VERSION 5.7 ;
BUSBITCHARS "[]" ;
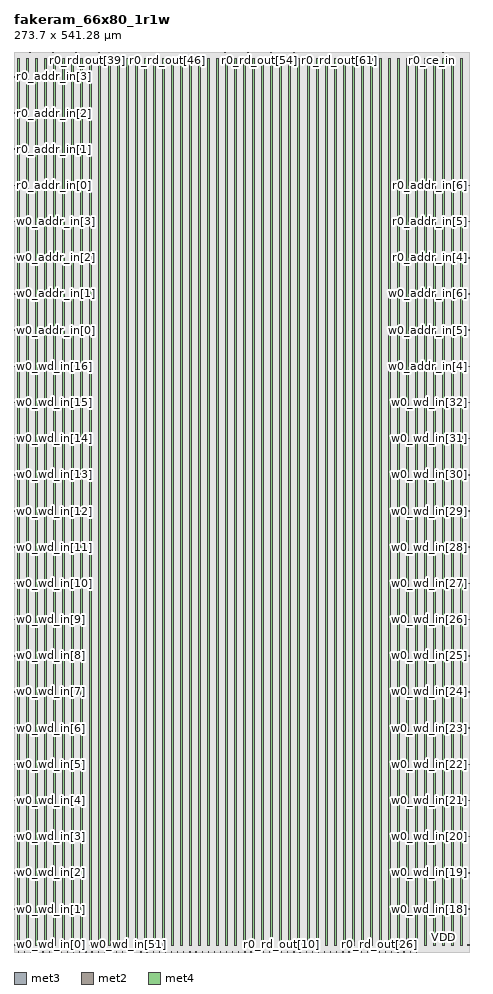
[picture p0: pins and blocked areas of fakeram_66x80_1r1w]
MACRO fakeram_66x80_1r1w
  FOREIGN fakeram_66x80_1r1w 0 0 ;
  SYMMETRY X Y R90 ;
  SIZE 273.700 BY 541.280 ;
  CLASS BLOCK ;
  PIN w0_wd_in[0]
    DIRECTION INPUT ;
    USE SIGNAL ;
    SHAPE ABUTMENT ;
    PORT
      LAYER met3 ;
      RECT 0.000 3.930 0.900 4.230 ;
    END
  END w0_wd_in[0]
  PIN w0_wd_in[1]
    DIRECTION INPUT ;
    USE SIGNAL ;
    SHAPE ABUTMENT ;
    PORT
      LAYER met3 ;
      RECT 0.000 25.690 0.900 25.990 ;
    END
  END w0_wd_in[1]
  PIN w0_wd_in[2]
    DIRECTION INPUT ;
    USE SIGNAL ;
    SHAPE ABUTMENT ;
    PORT
      LAYER met3 ;
      RECT 0.000 47.450 0.900 47.750 ;
    END
  END w0_wd_in[2]
  PIN w0_wd_in[3]
    DIRECTION INPUT ;
    USE SIGNAL ;
    SHAPE ABUTMENT ;
    PORT
      LAYER met3 ;
      RECT 0.000 69.210 0.900 69.510 ;
    END
  END w0_wd_in[3]
  PIN w0_wd_in[4]
    DIRECTION INPUT ;
    USE SIGNAL ;
    SHAPE ABUTMENT ;
    PORT
      LAYER met3 ;
      RECT 0.000 90.970 0.900 91.270 ;
    END
  END w0_wd_in[4]
  PIN w0_wd_in[5]
    DIRECTION INPUT ;
    USE SIGNAL ;
    SHAPE ABUTMENT ;
    PORT
      LAYER met3 ;
      RECT 0.000 112.730 0.900 113.030 ;
    END
  END w0_wd_in[5]
  PIN w0_wd_in[6]
    DIRECTION INPUT ;
    USE SIGNAL ;
    SHAPE ABUTMENT ;
    PORT
      LAYER met3 ;
      RECT 0.000 134.490 0.900 134.790 ;
    END
  END w0_wd_in[6]
  PIN w0_wd_in[7]
    DIRECTION INPUT ;
    USE SIGNAL ;
    SHAPE ABUTMENT ;
    PORT
      LAYER met3 ;
      RECT 0.000 156.250 0.900 156.550 ;
    END
  END w0_wd_in[7]
  PIN w0_wd_in[8]
    DIRECTION INPUT ;
    USE SIGNAL ;
    SHAPE ABUTMENT ;
    PORT
      LAYER met3 ;
      RECT 0.000 178.010 0.900 178.310 ;
    END
  END w0_wd_in[8]
  PIN w0_wd_in[9]
    DIRECTION INPUT ;
    USE SIGNAL ;
    SHAPE ABUTMENT ;
    PORT
      LAYER met3 ;
      RECT 0.000 199.770 0.900 200.070 ;
    END
  END w0_wd_in[9]
  PIN w0_wd_in[10]
    DIRECTION INPUT ;
    USE SIGNAL ;
    SHAPE ABUTMENT ;
    PORT
      LAYER met3 ;
      RECT 0.000 221.530 0.900 221.830 ;
    END
  END w0_wd_in[10]
  PIN w0_wd_in[11]
    DIRECTION INPUT ;
    USE SIGNAL ;
    SHAPE ABUTMENT ;
    PORT
      LAYER met3 ;
      RECT 0.000 243.290 0.900 243.590 ;
    END
  END w0_wd_in[11]
  PIN w0_wd_in[12]
    DIRECTION INPUT ;
    USE SIGNAL ;
    SHAPE ABUTMENT ;
    PORT
      LAYER met3 ;
      RECT 0.000 265.050 0.900 265.350 ;
    END
  END w0_wd_in[12]
  PIN w0_wd_in[13]
    DIRECTION INPUT ;
    USE SIGNAL ;
    SHAPE ABUTMENT ;
    PORT
      LAYER met3 ;
      RECT 0.000 286.810 0.900 287.110 ;
    END
  END w0_wd_in[13]
  PIN w0_wd_in[14]
    DIRECTION INPUT ;
    USE SIGNAL ;
    SHAPE ABUTMENT ;
    PORT
      LAYER met3 ;
      RECT 0.000 308.570 0.900 308.870 ;
    END
  END w0_wd_in[14]
  PIN w0_wd_in[15]
    DIRECTION INPUT ;
    USE SIGNAL ;
    SHAPE ABUTMENT ;
    PORT
      LAYER met3 ;
      RECT 0.000 330.330 0.900 330.630 ;
    END
  END w0_wd_in[15]
  PIN w0_wd_in[16]
    DIRECTION INPUT ;
    USE SIGNAL ;
    SHAPE ABUTMENT ;
    PORT
      LAYER met3 ;
      RECT 0.000 352.090 0.900 352.390 ;
    END
  END w0_wd_in[16]
  PIN w0_wd_in[17]
    DIRECTION INPUT ;
    USE SIGNAL ;
    SHAPE ABUTMENT ;
    PORT
      LAYER met3 ;
      RECT 272.800 3.930 273.700 4.230 ;
    END
  END w0_wd_in[17]
  PIN w0_wd_in[18]
    DIRECTION INPUT ;
    USE SIGNAL ;
    SHAPE ABUTMENT ;
    PORT
      LAYER met3 ;
      RECT 272.800 25.690 273.700 25.990 ;
    END
  END w0_wd_in[18]
  PIN w0_wd_in[19]
    DIRECTION INPUT ;
    USE SIGNAL ;
    SHAPE ABUTMENT ;
    PORT
      LAYER met3 ;
      RECT 272.800 47.450 273.700 47.750 ;
    END
  END w0_wd_in[19]
  PIN w0_wd_in[20]
    DIRECTION INPUT ;
    USE SIGNAL ;
    SHAPE ABUTMENT ;
    PORT
      LAYER met3 ;
      RECT 272.800 69.210 273.700 69.510 ;
    END
  END w0_wd_in[20]
  PIN w0_wd_in[21]
    DIRECTION INPUT ;
    USE SIGNAL ;
    SHAPE ABUTMENT ;
    PORT
      LAYER met3 ;
      RECT 272.800 90.970 273.700 91.270 ;
    END
  END w0_wd_in[21]
  PIN w0_wd_in[22]
    DIRECTION INPUT ;
    USE SIGNAL ;
    SHAPE ABUTMENT ;
    PORT
      LAYER met3 ;
      RECT 272.800 112.730 273.700 113.030 ;
    END
  END w0_wd_in[22]
  PIN w0_wd_in[23]
    DIRECTION INPUT ;
    USE SIGNAL ;
    SHAPE ABUTMENT ;
    PORT
      LAYER met3 ;
      RECT 272.800 134.490 273.700 134.790 ;
    END
  END w0_wd_in[23]
  PIN w0_wd_in[24]
    DIRECTION INPUT ;
    USE SIGNAL ;
    SHAPE ABUTMENT ;
    PORT
      LAYER met3 ;
      RECT 272.800 156.250 273.700 156.550 ;
    END
  END w0_wd_in[24]
  PIN w0_wd_in[25]
    DIRECTION INPUT ;
    USE SIGNAL ;
    SHAPE ABUTMENT ;
    PORT
      LAYER met3 ;
      RECT 272.800 178.010 273.700 178.310 ;
    END
  END w0_wd_in[25]
  PIN w0_wd_in[26]
    DIRECTION INPUT ;
    USE SIGNAL ;
    SHAPE ABUTMENT ;
    PORT
      LAYER met3 ;
      RECT 272.800 199.770 273.700 200.070 ;
    END
  END w0_wd_in[26]
  PIN w0_wd_in[27]
    DIRECTION INPUT ;
    USE SIGNAL ;
    SHAPE ABUTMENT ;
    PORT
      LAYER met3 ;
      RECT 272.800 221.530 273.700 221.830 ;
    END
  END w0_wd_in[27]
  PIN w0_wd_in[28]
    DIRECTION INPUT ;
    USE SIGNAL ;
    SHAPE ABUTMENT ;
    PORT
      LAYER met3 ;
      RECT 272.800 243.290 273.700 243.590 ;
    END
  END w0_wd_in[28]
  PIN w0_wd_in[29]
    DIRECTION INPUT ;
    USE SIGNAL ;
    SHAPE ABUTMENT ;
    PORT
      LAYER met3 ;
      RECT 272.800 265.050 273.700 265.350 ;
    END
  END w0_wd_in[29]
  PIN w0_wd_in[30]
    DIRECTION INPUT ;
    USE SIGNAL ;
    SHAPE ABUTMENT ;
    PORT
      LAYER met3 ;
      RECT 272.800 286.810 273.700 287.110 ;
    END
  END w0_wd_in[30]
  PIN w0_wd_in[31]
    DIRECTION INPUT ;
    USE SIGNAL ;
    SHAPE ABUTMENT ;
    PORT
      LAYER met3 ;
      RECT 272.800 308.570 273.700 308.870 ;
    END
  END w0_wd_in[31]
  PIN w0_wd_in[32]
    DIRECTION INPUT ;
    USE SIGNAL ;
    SHAPE ABUTMENT ;
    PORT
      LAYER met3 ;
      RECT 272.800 330.330 273.700 330.630 ;
    END
  END w0_wd_in[32]
  PIN w0_wd_in[33]
    DIRECTION INPUT ;
    USE SIGNAL ;
    SHAPE ABUTMENT ;
    PORT
      LAYER met2 ;
      RECT 2.690 0.000 2.830 0.420 ;
    END
  END w0_wd_in[33]
  PIN w0_wd_in[34]
    DIRECTION INPUT ;
    USE SIGNAL ;
    SHAPE ABUTMENT ;
    PORT
      LAYER met2 ;
      RECT 6.370 0.000 6.510 0.420 ;
    END
  END w0_wd_in[34]
  PIN w0_wd_in[35]
    DIRECTION INPUT ;
    USE SIGNAL ;
    SHAPE ABUTMENT ;
    PORT
      LAYER met2 ;
      RECT 10.050 0.000 10.190 0.420 ;
    END
  END w0_wd_in[35]
  PIN w0_wd_in[36]
    DIRECTION INPUT ;
    USE SIGNAL ;
    SHAPE ABUTMENT ;
    PORT
      LAYER met2 ;
      RECT 13.730 0.000 13.870 0.420 ;
    END
  END w0_wd_in[36]
  PIN w0_wd_in[37]
    DIRECTION INPUT ;
    USE SIGNAL ;
    SHAPE ABUTMENT ;
    PORT
      LAYER met2 ;
      RECT 17.410 0.000 17.550 0.420 ;
    END
  END w0_wd_in[37]
  PIN w0_wd_in[38]
    DIRECTION INPUT ;
    USE SIGNAL ;
    SHAPE ABUTMENT ;
    PORT
      LAYER met2 ;
      RECT 21.090 0.000 21.230 0.420 ;
    END
  END w0_wd_in[38]
  PIN w0_wd_in[39]
    DIRECTION INPUT ;
    USE SIGNAL ;
    SHAPE ABUTMENT ;
    PORT
      LAYER met2 ;
      RECT 24.770 0.000 24.910 0.420 ;
    END
  END w0_wd_in[39]
  PIN w0_wd_in[40]
    DIRECTION INPUT ;
    USE SIGNAL ;
    SHAPE ABUTMENT ;
    PORT
      LAYER met2 ;
      RECT 28.450 0.000 28.590 0.420 ;
    END
  END w0_wd_in[40]
  PIN w0_wd_in[41]
    DIRECTION INPUT ;
    USE SIGNAL ;
    SHAPE ABUTMENT ;
    PORT
      LAYER met2 ;
      RECT 32.130 0.000 32.270 0.420 ;
    END
  END w0_wd_in[41]
  PIN w0_wd_in[42]
    DIRECTION INPUT ;
    USE SIGNAL ;
    SHAPE ABUTMENT ;
    PORT
      LAYER met2 ;
      RECT 35.810 0.000 35.950 0.420 ;
    END
  END w0_wd_in[42]
  PIN w0_wd_in[43]
    DIRECTION INPUT ;
    USE SIGNAL ;
    SHAPE ABUTMENT ;
    PORT
      LAYER met2 ;
      RECT 39.490 0.000 39.630 0.420 ;
    END
  END w0_wd_in[43]
  PIN w0_wd_in[44]
    DIRECTION INPUT ;
    USE SIGNAL ;
    SHAPE ABUTMENT ;
    PORT
      LAYER met2 ;
      RECT 43.170 0.000 43.310 0.420 ;
    END
  END w0_wd_in[44]
  PIN w0_wd_in[45]
    DIRECTION INPUT ;
    USE SIGNAL ;
    SHAPE ABUTMENT ;
    PORT
      LAYER met2 ;
      RECT 46.850 0.000 46.990 0.420 ;
    END
  END w0_wd_in[45]
  PIN w0_wd_in[46]
    DIRECTION INPUT ;
    USE SIGNAL ;
    SHAPE ABUTMENT ;
    PORT
      LAYER met2 ;
      RECT 50.530 0.000 50.670 0.420 ;
    END
  END w0_wd_in[46]
  PIN w0_wd_in[47]
    DIRECTION INPUT ;
    USE SIGNAL ;
    SHAPE ABUTMENT ;
    PORT
      LAYER met2 ;
      RECT 54.210 0.000 54.350 0.420 ;
    END
  END w0_wd_in[47]
  PIN w0_wd_in[48]
    DIRECTION INPUT ;
    USE SIGNAL ;
    SHAPE ABUTMENT ;
    PORT
      LAYER met2 ;
      RECT 57.890 0.000 58.030 0.420 ;
    END
  END w0_wd_in[48]
  PIN w0_wd_in[49]
    DIRECTION INPUT ;
    USE SIGNAL ;
    SHAPE ABUTMENT ;
    PORT
      LAYER met2 ;
      RECT 61.570 0.000 61.710 0.420 ;
    END
  END w0_wd_in[49]
  PIN w0_wd_in[50]
    DIRECTION INPUT ;
    USE SIGNAL ;
    SHAPE ABUTMENT ;
    PORT
      LAYER met2 ;
      RECT 65.250 0.000 65.390 0.420 ;
    END
  END w0_wd_in[50]
  PIN w0_wd_in[51]
    DIRECTION INPUT ;
    USE SIGNAL ;
    SHAPE ABUTMENT ;
    PORT
      LAYER met2 ;
      RECT 68.930 0.000 69.070 0.420 ;
    END
  END w0_wd_in[51]
  PIN w0_wd_in[52]
    DIRECTION INPUT ;
    USE SIGNAL ;
    SHAPE ABUTMENT ;
    PORT
      LAYER met2 ;
      RECT 72.610 0.000 72.750 0.420 ;
    END
  END w0_wd_in[52]
  PIN w0_wd_in[53]
    DIRECTION INPUT ;
    USE SIGNAL ;
    SHAPE ABUTMENT ;
    PORT
      LAYER met2 ;
      RECT 76.290 0.000 76.430 0.420 ;
    END
  END w0_wd_in[53]
  PIN w0_wd_in[54]
    DIRECTION INPUT ;
    USE SIGNAL ;
    SHAPE ABUTMENT ;
    PORT
      LAYER met2 ;
      RECT 79.970 0.000 80.110 0.420 ;
    END
  END w0_wd_in[54]
  PIN w0_wd_in[55]
    DIRECTION INPUT ;
    USE SIGNAL ;
    SHAPE ABUTMENT ;
    PORT
      LAYER met2 ;
      RECT 83.650 0.000 83.790 0.420 ;
    END
  END w0_wd_in[55]
  PIN w0_wd_in[56]
    DIRECTION INPUT ;
    USE SIGNAL ;
    SHAPE ABUTMENT ;
    PORT
      LAYER met2 ;
      RECT 87.330 0.000 87.470 0.420 ;
    END
  END w0_wd_in[56]
  PIN w0_wd_in[57]
    DIRECTION INPUT ;
    USE SIGNAL ;
    SHAPE ABUTMENT ;
    PORT
      LAYER met2 ;
      RECT 91.010 0.000 91.150 0.420 ;
    END
  END w0_wd_in[57]
  PIN w0_wd_in[58]
    DIRECTION INPUT ;
    USE SIGNAL ;
    SHAPE ABUTMENT ;
    PORT
      LAYER met2 ;
      RECT 94.690 0.000 94.830 0.420 ;
    END
  END w0_wd_in[58]
  PIN w0_wd_in[59]
    DIRECTION INPUT ;
    USE SIGNAL ;
    SHAPE ABUTMENT ;
    PORT
      LAYER met2 ;
      RECT 98.370 0.000 98.510 0.420 ;
    END
  END w0_wd_in[59]
  PIN w0_wd_in[60]
    DIRECTION INPUT ;
    USE SIGNAL ;
    SHAPE ABUTMENT ;
    PORT
      LAYER met2 ;
      RECT 102.050 0.000 102.190 0.420 ;
    END
  END w0_wd_in[60]
  PIN w0_wd_in[61]
    DIRECTION INPUT ;
    USE SIGNAL ;
    SHAPE ABUTMENT ;
    PORT
      LAYER met2 ;
      RECT 105.730 0.000 105.870 0.420 ;
    END
  END w0_wd_in[61]
  PIN w0_wd_in[62]
    DIRECTION INPUT ;
    USE SIGNAL ;
    SHAPE ABUTMENT ;
    PORT
      LAYER met2 ;
      RECT 109.410 0.000 109.550 0.420 ;
    END
  END w0_wd_in[62]
  PIN w0_wd_in[63]
    DIRECTION INPUT ;
    USE SIGNAL ;
    SHAPE ABUTMENT ;
    PORT
      LAYER met2 ;
      RECT 113.090 0.000 113.230 0.420 ;
    END
  END w0_wd_in[63]
  PIN w0_wd_in[64]
    DIRECTION INPUT ;
    USE SIGNAL ;
    SHAPE ABUTMENT ;
    PORT
      LAYER met2 ;
      RECT 116.770 0.000 116.910 0.420 ;
    END
  END w0_wd_in[64]
  PIN w0_wd_in[65]
    DIRECTION INPUT ;
    USE SIGNAL ;
    SHAPE ABUTMENT ;
    PORT
      LAYER met2 ;
      RECT 120.450 0.000 120.590 0.420 ;
    END
  END w0_wd_in[65]
  PIN r0_rd_out[0]
    DIRECTION OUTPUT ;
    USE SIGNAL ;
    SHAPE ABUTMENT ;
    PORT
      LAYER met2 ;
      RECT 124.130 0.000 124.270 0.420 ;
    END
  END r0_rd_out[0]
  PIN r0_rd_out[1]
    DIRECTION OUTPUT ;
    USE SIGNAL ;
    SHAPE ABUTMENT ;
    PORT
      LAYER met2 ;
      RECT 127.810 0.000 127.950 0.420 ;
    END
  END r0_rd_out[1]
  PIN r0_rd_out[2]
    DIRECTION OUTPUT ;
    USE SIGNAL ;
    SHAPE ABUTMENT ;
    PORT
      LAYER met2 ;
      RECT 131.490 0.000 131.630 0.420 ;
    END
  END r0_rd_out[2]
  PIN r0_rd_out[3]
    DIRECTION OUTPUT ;
    USE SIGNAL ;
    SHAPE ABUTMENT ;
    PORT
      LAYER met2 ;
      RECT 135.170 0.000 135.310 0.420 ;
    END
  END r0_rd_out[3]
  PIN r0_rd_out[4]
    DIRECTION OUTPUT ;
    USE SIGNAL ;
    SHAPE ABUTMENT ;
    PORT
      LAYER met2 ;
      RECT 138.850 0.000 138.990 0.420 ;
    END
  END r0_rd_out[4]
  PIN r0_rd_out[5]
    DIRECTION OUTPUT ;
    USE SIGNAL ;
    SHAPE ABUTMENT ;
    PORT
      LAYER met2 ;
      RECT 142.530 0.000 142.670 0.420 ;
    END
  END r0_rd_out[5]
  PIN r0_rd_out[6]
    DIRECTION OUTPUT ;
    USE SIGNAL ;
    SHAPE ABUTMENT ;
    PORT
      LAYER met2 ;
      RECT 146.210 0.000 146.350 0.420 ;
    END
  END r0_rd_out[6]
  PIN r0_rd_out[7]
    DIRECTION OUTPUT ;
    USE SIGNAL ;
    SHAPE ABUTMENT ;
    PORT
      LAYER met2 ;
      RECT 149.890 0.000 150.030 0.420 ;
    END
  END r0_rd_out[7]
  PIN r0_rd_out[8]
    DIRECTION OUTPUT ;
    USE SIGNAL ;
    SHAPE ABUTMENT ;
    PORT
      LAYER met2 ;
      RECT 153.570 0.000 153.710 0.420 ;
    END
  END r0_rd_out[8]
  PIN r0_rd_out[9]
    DIRECTION OUTPUT ;
    USE SIGNAL ;
    SHAPE ABUTMENT ;
    PORT
      LAYER met2 ;
      RECT 157.250 0.000 157.390 0.420 ;
    END
  END r0_rd_out[9]
  PIN r0_rd_out[10]
    DIRECTION OUTPUT ;
    USE SIGNAL ;
    SHAPE ABUTMENT ;
    PORT
      LAYER met2 ;
      RECT 160.930 0.000 161.070 0.420 ;
    END
  END r0_rd_out[10]
  PIN r0_rd_out[11]
    DIRECTION OUTPUT ;
    USE SIGNAL ;
    SHAPE ABUTMENT ;
    PORT
      LAYER met2 ;
      RECT 164.610 0.000 164.750 0.420 ;
    END
  END r0_rd_out[11]
  PIN r0_rd_out[12]
    DIRECTION OUTPUT ;
    USE SIGNAL ;
    SHAPE ABUTMENT ;
    PORT
      LAYER met2 ;
      RECT 168.290 0.000 168.430 0.420 ;
    END
  END r0_rd_out[12]
  PIN r0_rd_out[13]
    DIRECTION OUTPUT ;
    USE SIGNAL ;
    SHAPE ABUTMENT ;
    PORT
      LAYER met2 ;
      RECT 171.970 0.000 172.110 0.420 ;
    END
  END r0_rd_out[13]
  PIN r0_rd_out[14]
    DIRECTION OUTPUT ;
    USE SIGNAL ;
    SHAPE ABUTMENT ;
    PORT
      LAYER met2 ;
      RECT 175.650 0.000 175.790 0.420 ;
    END
  END r0_rd_out[14]
  PIN r0_rd_out[15]
    DIRECTION OUTPUT ;
    USE SIGNAL ;
    SHAPE ABUTMENT ;
    PORT
      LAYER met2 ;
      RECT 179.330 0.000 179.470 0.420 ;
    END
  END r0_rd_out[15]
  PIN r0_rd_out[16]
    DIRECTION OUTPUT ;
    USE SIGNAL ;
    SHAPE ABUTMENT ;
    PORT
      LAYER met2 ;
      RECT 183.010 0.000 183.150 0.420 ;
    END
  END r0_rd_out[16]
  PIN r0_rd_out[17]
    DIRECTION OUTPUT ;
    USE SIGNAL ;
    SHAPE ABUTMENT ;
    PORT
      LAYER met2 ;
      RECT 186.690 0.000 186.830 0.420 ;
    END
  END r0_rd_out[17]
  PIN r0_rd_out[18]
    DIRECTION OUTPUT ;
    USE SIGNAL ;
    SHAPE ABUTMENT ;
    PORT
      LAYER met2 ;
      RECT 190.370 0.000 190.510 0.420 ;
    END
  END r0_rd_out[18]
  PIN r0_rd_out[19]
    DIRECTION OUTPUT ;
    USE SIGNAL ;
    SHAPE ABUTMENT ;
    PORT
      LAYER met2 ;
      RECT 194.050 0.000 194.190 0.420 ;
    END
  END r0_rd_out[19]
  PIN r0_rd_out[20]
    DIRECTION OUTPUT ;
    USE SIGNAL ;
    SHAPE ABUTMENT ;
    PORT
      LAYER met2 ;
      RECT 197.730 0.000 197.870 0.420 ;
    END
  END r0_rd_out[20]
  PIN r0_rd_out[21]
    DIRECTION OUTPUT ;
    USE SIGNAL ;
    SHAPE ABUTMENT ;
    PORT
      LAYER met2 ;
      RECT 201.410 0.000 201.550 0.420 ;
    END
  END r0_rd_out[21]
  PIN r0_rd_out[22]
    DIRECTION OUTPUT ;
    USE SIGNAL ;
    SHAPE ABUTMENT ;
    PORT
      LAYER met2 ;
      RECT 205.090 0.000 205.230 0.420 ;
    END
  END r0_rd_out[22]
  PIN r0_rd_out[23]
    DIRECTION OUTPUT ;
    USE SIGNAL ;
    SHAPE ABUTMENT ;
    PORT
      LAYER met2 ;
      RECT 208.770 0.000 208.910 0.420 ;
    END
  END r0_rd_out[23]
  PIN r0_rd_out[24]
    DIRECTION OUTPUT ;
    USE SIGNAL ;
    SHAPE ABUTMENT ;
    PORT
      LAYER met2 ;
      RECT 212.450 0.000 212.590 0.420 ;
    END
  END r0_rd_out[24]
  PIN r0_rd_out[25]
    DIRECTION OUTPUT ;
    USE SIGNAL ;
    SHAPE ABUTMENT ;
    PORT
      LAYER met2 ;
      RECT 216.130 0.000 216.270 0.420 ;
    END
  END r0_rd_out[25]
  PIN r0_rd_out[26]
    DIRECTION OUTPUT ;
    USE SIGNAL ;
    SHAPE ABUTMENT ;
    PORT
      LAYER met2 ;
      RECT 219.810 0.000 219.950 0.420 ;
    END
  END r0_rd_out[26]
  PIN r0_rd_out[27]
    DIRECTION OUTPUT ;
    USE SIGNAL ;
    SHAPE ABUTMENT ;
    PORT
      LAYER met2 ;
      RECT 223.490 0.000 223.630 0.420 ;
    END
  END r0_rd_out[27]
  PIN r0_rd_out[28]
    DIRECTION OUTPUT ;
    USE SIGNAL ;
    SHAPE ABUTMENT ;
    PORT
      LAYER met2 ;
      RECT 227.170 0.000 227.310 0.420 ;
    END
  END r0_rd_out[28]
  PIN r0_rd_out[29]
    DIRECTION OUTPUT ;
    USE SIGNAL ;
    SHAPE ABUTMENT ;
    PORT
      LAYER met2 ;
      RECT 230.850 0.000 230.990 0.420 ;
    END
  END r0_rd_out[29]
  PIN r0_rd_out[30]
    DIRECTION OUTPUT ;
    USE SIGNAL ;
    SHAPE ABUTMENT ;
    PORT
      LAYER met2 ;
      RECT 234.530 0.000 234.670 0.420 ;
    END
  END r0_rd_out[30]
  PIN r0_rd_out[31]
    DIRECTION OUTPUT ;
    USE SIGNAL ;
    SHAPE ABUTMENT ;
    PORT
      LAYER met2 ;
      RECT 238.210 0.000 238.350 0.420 ;
    END
  END r0_rd_out[31]
  PIN r0_rd_out[32]
    DIRECTION OUTPUT ;
    USE SIGNAL ;
    SHAPE ABUTMENT ;
    PORT
      LAYER met2 ;
      RECT 241.890 0.000 242.030 0.420 ;
    END
  END r0_rd_out[32]
  PIN r0_rd_out[33]
    DIRECTION OUTPUT ;
    USE SIGNAL ;
    SHAPE ABUTMENT ;
    PORT
      LAYER met2 ;
      RECT 2.690 540.860 2.830 541.280 ;
    END
  END r0_rd_out[33]
  PIN r0_rd_out[34]
    DIRECTION OUTPUT ;
    USE SIGNAL ;
    SHAPE ABUTMENT ;
    PORT
      LAYER met2 ;
      RECT 9.590 540.860 9.730 541.280 ;
    END
  END r0_rd_out[34]
  PIN r0_rd_out[35]
    DIRECTION OUTPUT ;
    USE SIGNAL ;
    SHAPE ABUTMENT ;
    PORT
      LAYER met2 ;
      RECT 16.490 540.860 16.630 541.280 ;
    END
  END r0_rd_out[35]
  PIN r0_rd_out[36]
    DIRECTION OUTPUT ;
    USE SIGNAL ;
    SHAPE ABUTMENT ;
    PORT
      LAYER met2 ;
      RECT 23.390 540.860 23.530 541.280 ;
    END
  END r0_rd_out[36]
  PIN r0_rd_out[37]
    DIRECTION OUTPUT ;
    USE SIGNAL ;
    SHAPE ABUTMENT ;
    PORT
      LAYER met2 ;
      RECT 30.290 540.860 30.430 541.280 ;
    END
  END r0_rd_out[37]
  PIN r0_rd_out[38]
    DIRECTION OUTPUT ;
    USE SIGNAL ;
    SHAPE ABUTMENT ;
    PORT
      LAYER met2 ;
      RECT 37.190 540.860 37.330 541.280 ;
    END
  END r0_rd_out[38]
  PIN r0_rd_out[39]
    DIRECTION OUTPUT ;
    USE SIGNAL ;
    SHAPE ABUTMENT ;
    PORT
      LAYER met2 ;
      RECT 44.090 540.860 44.230 541.280 ;
    END
  END r0_rd_out[39]
  PIN r0_rd_out[40]
    DIRECTION OUTPUT ;
    USE SIGNAL ;
    SHAPE ABUTMENT ;
    PORT
      LAYER met2 ;
      RECT 50.990 540.860 51.130 541.280 ;
    END
  END r0_rd_out[40]
  PIN r0_rd_out[41]
    DIRECTION OUTPUT ;
    USE SIGNAL ;
    SHAPE ABUTMENT ;
    PORT
      LAYER met2 ;
      RECT 57.890 540.860 58.030 541.280 ;
    END
  END r0_rd_out[41]
  PIN r0_rd_out[42]
    DIRECTION OUTPUT ;
    USE SIGNAL ;
    SHAPE ABUTMENT ;
    PORT
      LAYER met2 ;
      RECT 64.790 540.860 64.930 541.280 ;
    END
  END r0_rd_out[42]
  PIN r0_rd_out[43]
    DIRECTION OUTPUT ;
    USE SIGNAL ;
    SHAPE ABUTMENT ;
    PORT
      LAYER met2 ;
      RECT 71.690 540.860 71.830 541.280 ;
    END
  END r0_rd_out[43]
  PIN r0_rd_out[44]
    DIRECTION OUTPUT ;
    USE SIGNAL ;
    SHAPE ABUTMENT ;
    PORT
      LAYER met2 ;
      RECT 78.590 540.860 78.730 541.280 ;
    END
  END r0_rd_out[44]
  PIN r0_rd_out[45]
    DIRECTION OUTPUT ;
    USE SIGNAL ;
    SHAPE ABUTMENT ;
    PORT
      LAYER met2 ;
      RECT 85.490 540.860 85.630 541.280 ;
    END
  END r0_rd_out[45]
  PIN r0_rd_out[46]
    DIRECTION OUTPUT ;
    USE SIGNAL ;
    SHAPE ABUTMENT ;
    PORT
      LAYER met2 ;
      RECT 92.390 540.860 92.530 541.280 ;
    END
  END r0_rd_out[46]
  PIN r0_rd_out[47]
    DIRECTION OUTPUT ;
    USE SIGNAL ;
    SHAPE ABUTMENT ;
    PORT
      LAYER met2 ;
      RECT 99.290 540.860 99.430 541.280 ;
    END
  END r0_rd_out[47]
  PIN r0_rd_out[48]
    DIRECTION OUTPUT ;
    USE SIGNAL ;
    SHAPE ABUTMENT ;
    PORT
      LAYER met2 ;
      RECT 106.190 540.860 106.330 541.280 ;
    END
  END r0_rd_out[48]
  PIN r0_rd_out[49]
    DIRECTION OUTPUT ;
    USE SIGNAL ;
    SHAPE ABUTMENT ;
    PORT
      LAYER met2 ;
      RECT 113.090 540.860 113.230 541.280 ;
    END
  END r0_rd_out[49]
  PIN r0_rd_out[50]
    DIRECTION OUTPUT ;
    USE SIGNAL ;
    SHAPE ABUTMENT ;
    PORT
      LAYER met2 ;
      RECT 119.990 540.860 120.130 541.280 ;
    END
  END r0_rd_out[50]
  PIN r0_rd_out[51]
    DIRECTION OUTPUT ;
    USE SIGNAL ;
    SHAPE ABUTMENT ;
    PORT
      LAYER met2 ;
      RECT 126.890 540.860 127.030 541.280 ;
    END
  END r0_rd_out[51]
  PIN r0_rd_out[52]
    DIRECTION OUTPUT ;
    USE SIGNAL ;
    SHAPE ABUTMENT ;
    PORT
      LAYER met2 ;
      RECT 133.790 540.860 133.930 541.280 ;
    END
  END r0_rd_out[52]
  PIN r0_rd_out[53]
    DIRECTION OUTPUT ;
    USE SIGNAL ;
    SHAPE ABUTMENT ;
    PORT
      LAYER met2 ;
      RECT 140.690 540.860 140.830 541.280 ;
    END
  END r0_rd_out[53]
  PIN r0_rd_out[54]
    DIRECTION OUTPUT ;
    USE SIGNAL ;
    SHAPE ABUTMENT ;
    PORT
      LAYER met2 ;
      RECT 147.590 540.860 147.730 541.280 ;
    END
  END r0_rd_out[54]
  PIN r0_rd_out[55]
    DIRECTION OUTPUT ;
    USE SIGNAL ;
    SHAPE ABUTMENT ;
    PORT
      LAYER met2 ;
      RECT 154.490 540.860 154.630 541.280 ;
    END
  END r0_rd_out[55]
  PIN r0_rd_out[56]
    DIRECTION OUTPUT ;
    USE SIGNAL ;
    SHAPE ABUTMENT ;
    PORT
      LAYER met2 ;
      RECT 161.390 540.860 161.530 541.280 ;
    END
  END r0_rd_out[56]
  PIN r0_rd_out[57]
    DIRECTION OUTPUT ;
    USE SIGNAL ;
    SHAPE ABUTMENT ;
    PORT
      LAYER met2 ;
      RECT 168.290 540.860 168.430 541.280 ;
    END
  END r0_rd_out[57]
  PIN r0_rd_out[58]
    DIRECTION OUTPUT ;
    USE SIGNAL ;
    SHAPE ABUTMENT ;
    PORT
      LAYER met2 ;
      RECT 175.190 540.860 175.330 541.280 ;
    END
  END r0_rd_out[58]
  PIN r0_rd_out[59]
    DIRECTION OUTPUT ;
    USE SIGNAL ;
    SHAPE ABUTMENT ;
    PORT
      LAYER met2 ;
      RECT 182.090 540.860 182.230 541.280 ;
    END
  END r0_rd_out[59]
  PIN r0_rd_out[60]
    DIRECTION OUTPUT ;
    USE SIGNAL ;
    SHAPE ABUTMENT ;
    PORT
      LAYER met2 ;
      RECT 188.990 540.860 189.130 541.280 ;
    END
  END r0_rd_out[60]
  PIN r0_rd_out[61]
    DIRECTION OUTPUT ;
    USE SIGNAL ;
    SHAPE ABUTMENT ;
    PORT
      LAYER met2 ;
      RECT 195.890 540.860 196.030 541.280 ;
    END
  END r0_rd_out[61]
  PIN r0_rd_out[62]
    DIRECTION OUTPUT ;
    USE SIGNAL ;
    SHAPE ABUTMENT ;
    PORT
      LAYER met2 ;
      RECT 202.790 540.860 202.930 541.280 ;
    END
  END r0_rd_out[62]
  PIN r0_rd_out[63]
    DIRECTION OUTPUT ;
    USE SIGNAL ;
    SHAPE ABUTMENT ;
    PORT
      LAYER met2 ;
      RECT 209.690 540.860 209.830 541.280 ;
    END
  END r0_rd_out[63]
  PIN r0_rd_out[64]
    DIRECTION OUTPUT ;
    USE SIGNAL ;
    SHAPE ABUTMENT ;
    PORT
      LAYER met2 ;
      RECT 216.590 540.860 216.730 541.280 ;
    END
  END r0_rd_out[64]
  PIN r0_rd_out[65]
    DIRECTION OUTPUT ;
    USE SIGNAL ;
    SHAPE ABUTMENT ;
    PORT
      LAYER met2 ;
      RECT 223.490 540.860 223.630 541.280 ;
    END
  END r0_rd_out[65]
  PIN w0_addr_in[0]
    DIRECTION INPUT ;
    USE SIGNAL ;
    SHAPE ABUTMENT ;
    PORT
      LAYER met3 ;
      RECT 0.000 373.850 0.900 374.150 ;
    END
  END w0_addr_in[0]
  PIN w0_addr_in[1]
    DIRECTION INPUT ;
    USE SIGNAL ;
    SHAPE ABUTMENT ;
    PORT
      LAYER met3 ;
      RECT 0.000 395.610 0.900 395.910 ;
    END
  END w0_addr_in[1]
  PIN w0_addr_in[2]
    DIRECTION INPUT ;
    USE SIGNAL ;
    SHAPE ABUTMENT ;
    PORT
      LAYER met3 ;
      RECT 0.000 417.370 0.900 417.670 ;
    END
  END w0_addr_in[2]
  PIN w0_addr_in[3]
    DIRECTION INPUT ;
    USE SIGNAL ;
    SHAPE ABUTMENT ;
    PORT
      LAYER met3 ;
      RECT 0.000 439.130 0.900 439.430 ;
    END
  END w0_addr_in[3]
  PIN w0_addr_in[4]
    DIRECTION INPUT ;
    USE SIGNAL ;
    SHAPE ABUTMENT ;
    PORT
      LAYER met3 ;
      RECT 272.800 352.090 273.700 352.390 ;
    END
  END w0_addr_in[4]
  PIN w0_addr_in[5]
    DIRECTION INPUT ;
    USE SIGNAL ;
    SHAPE ABUTMENT ;
    PORT
      LAYER met3 ;
      RECT 272.800 373.850 273.700 374.150 ;
    END
  END w0_addr_in[5]
  PIN w0_addr_in[6]
    DIRECTION INPUT ;
    USE SIGNAL ;
    SHAPE ABUTMENT ;
    PORT
      LAYER met3 ;
      RECT 272.800 395.610 273.700 395.910 ;
    END
  END w0_addr_in[6]
  PIN r0_addr_in[0]
    DIRECTION INPUT ;
    USE SIGNAL ;
    SHAPE ABUTMENT ;
    PORT
      LAYER met3 ;
      RECT 0.000 460.890 0.900 461.190 ;
    END
  END r0_addr_in[0]
  PIN r0_addr_in[1]
    DIRECTION INPUT ;
    USE SIGNAL ;
    SHAPE ABUTMENT ;
    PORT
      LAYER met3 ;
      RECT 0.000 482.650 0.900 482.950 ;
    END
  END r0_addr_in[1]
  PIN r0_addr_in[2]
    DIRECTION INPUT ;
    USE SIGNAL ;
    SHAPE ABUTMENT ;
    PORT
      LAYER met3 ;
      RECT 0.000 504.410 0.900 504.710 ;
    END
  END r0_addr_in[2]
  PIN r0_addr_in[3]
    DIRECTION INPUT ;
    USE SIGNAL ;
    SHAPE ABUTMENT ;
    PORT
      LAYER met3 ;
      RECT 0.000 526.170 0.900 526.470 ;
    END
  END r0_addr_in[3]
  PIN r0_addr_in[4]
    DIRECTION INPUT ;
    USE SIGNAL ;
    SHAPE ABUTMENT ;
    PORT
      LAYER met3 ;
      RECT 272.800 417.370 273.700 417.670 ;
    END
  END r0_addr_in[4]
  PIN r0_addr_in[5]
    DIRECTION INPUT ;
    USE SIGNAL ;
    SHAPE ABUTMENT ;
    PORT
      LAYER met3 ;
      RECT 272.800 439.130 273.700 439.430 ;
    END
  END r0_addr_in[5]
  PIN r0_addr_in[6]
    DIRECTION INPUT ;
    USE SIGNAL ;
    SHAPE ABUTMENT ;
    PORT
      LAYER met3 ;
      RECT 272.800 460.890 273.700 461.190 ;
    END
  END r0_addr_in[6]
  PIN w0_we_in
    DIRECTION INPUT ;
    USE SIGNAL ;
    SHAPE ABUTMENT ;
    PORT
      LAYER met2 ;
      RECT 230.390 540.860 230.530 541.280 ;
    END
  END w0_we_in
  PIN w0_ce_in
    DIRECTION INPUT ;
    USE SIGNAL ;
    SHAPE ABUTMENT ;
    PORT
      LAYER met2 ;
      RECT 237.290 540.860 237.430 541.280 ;
    END
  END w0_ce_in
  PIN w0_clk
    DIRECTION INPUT ;
    USE SIGNAL ;
    SHAPE ABUTMENT ;
    PORT
      LAYER met2 ;
      RECT 244.190 540.860 244.330 541.280 ;
    END
  END w0_clk
  PIN r0_ce_in
    DIRECTION INPUT ;
    USE SIGNAL ;
    SHAPE ABUTMENT ;
    PORT
      LAYER met2 ;
      RECT 251.090 540.860 251.230 541.280 ;
    END
  END r0_ce_in
  PIN r0_clk
    DIRECTION INPUT ;
    USE SIGNAL ;
    SHAPE ABUTMENT ;
    PORT
      LAYER met2 ;
      RECT 257.990 540.860 258.130 541.280 ;
    END
  END r0_clk
  PIN VSS
    DIRECTION INOUT ;
    USE GROUND ;
    PORT
      LAYER met4 ;
      RECT 2.160 4.080 3.360 537.200 ;
      RECT 13.040 4.080 14.240 537.200 ;
      RECT 23.920 4.080 25.120 537.200 ;
      RECT 34.800 4.080 36.000 537.200 ;
      RECT 45.680 4.080 46.880 537.200 ;
      RECT 56.560 4.080 57.760 537.200 ;
      RECT 67.440 4.080 68.640 537.200 ;
      RECT 78.320 4.080 79.520 537.200 ;
      RECT 89.200 4.080 90.400 537.200 ;
      RECT 100.080 4.080 101.280 537.200 ;
      RECT 110.960 4.080 112.160 537.200 ;
      RECT 121.840 4.080 123.040 537.200 ;
      RECT 132.720 4.080 133.920 537.200 ;
      RECT 143.600 4.080 144.800 537.200 ;
      RECT 154.480 4.080 155.680 537.200 ;
      RECT 165.360 4.080 166.560 537.200 ;
      RECT 176.240 4.080 177.440 537.200 ;
      RECT 187.120 4.080 188.320 537.200 ;
      RECT 198.000 4.080 199.200 537.200 ;
      RECT 208.880 4.080 210.080 537.200 ;
      RECT 219.760 4.080 220.960 537.200 ;
      RECT 230.640 4.080 231.840 537.200 ;
      RECT 241.520 4.080 242.720 537.200 ;
      RECT 252.400 4.080 253.600 537.200 ;
      RECT 263.280 4.080 264.480 537.200 ;
    END
  END VSS
  PIN VDD
    DIRECTION INOUT ;
    USE POWER ;
    PORT
      LAYER met4 ;
      RECT 7.600 4.080 8.800 537.200 ;
      RECT 18.480 4.080 19.680 537.200 ;
      RECT 29.360 4.080 30.560 537.200 ;
      RECT 40.240 4.080 41.440 537.200 ;
      RECT 51.120 4.080 52.320 537.200 ;
      RECT 62.000 4.080 63.200 537.200 ;
      RECT 72.880 4.080 74.080 537.200 ;
      RECT 83.760 4.080 84.960 537.200 ;
      RECT 94.640 4.080 95.840 537.200 ;
      RECT 105.520 4.080 106.720 537.200 ;
      RECT 116.400 4.080 117.600 537.200 ;
      RECT 127.280 4.080 128.480 537.200 ;
      RECT 138.160 4.080 139.360 537.200 ;
      RECT 149.040 4.080 150.240 537.200 ;
      RECT 159.920 4.080 161.120 537.200 ;
      RECT 170.800 4.080 172.000 537.200 ;
      RECT 181.680 4.080 182.880 537.200 ;
      RECT 192.560 4.080 193.760 537.200 ;
      RECT 203.440 4.080 204.640 537.200 ;
      RECT 214.320 4.080 215.520 537.200 ;
      RECT 225.200 4.080 226.400 537.200 ;
      RECT 236.080 4.080 237.280 537.200 ;
      RECT 246.960 4.080 248.160 537.200 ;
      RECT 257.840 4.080 259.040 537.200 ;
      RECT 268.720 4.080 269.920 537.200 ;
    END
  END VDD
  OBS
    LAYER met1 ;
    RECT 0 0 273.700 541.280 ;
    LAYER met2 ;
    RECT 0 0 273.700 541.280 ;
    LAYER met3 ;
    RECT 0 0 273.700 541.280 ;
    LAYER met4 ;
    RECT 0 0 273.700 541.280 ;
  END
END fakeram_66x80_1r1w

END LIBRARY
